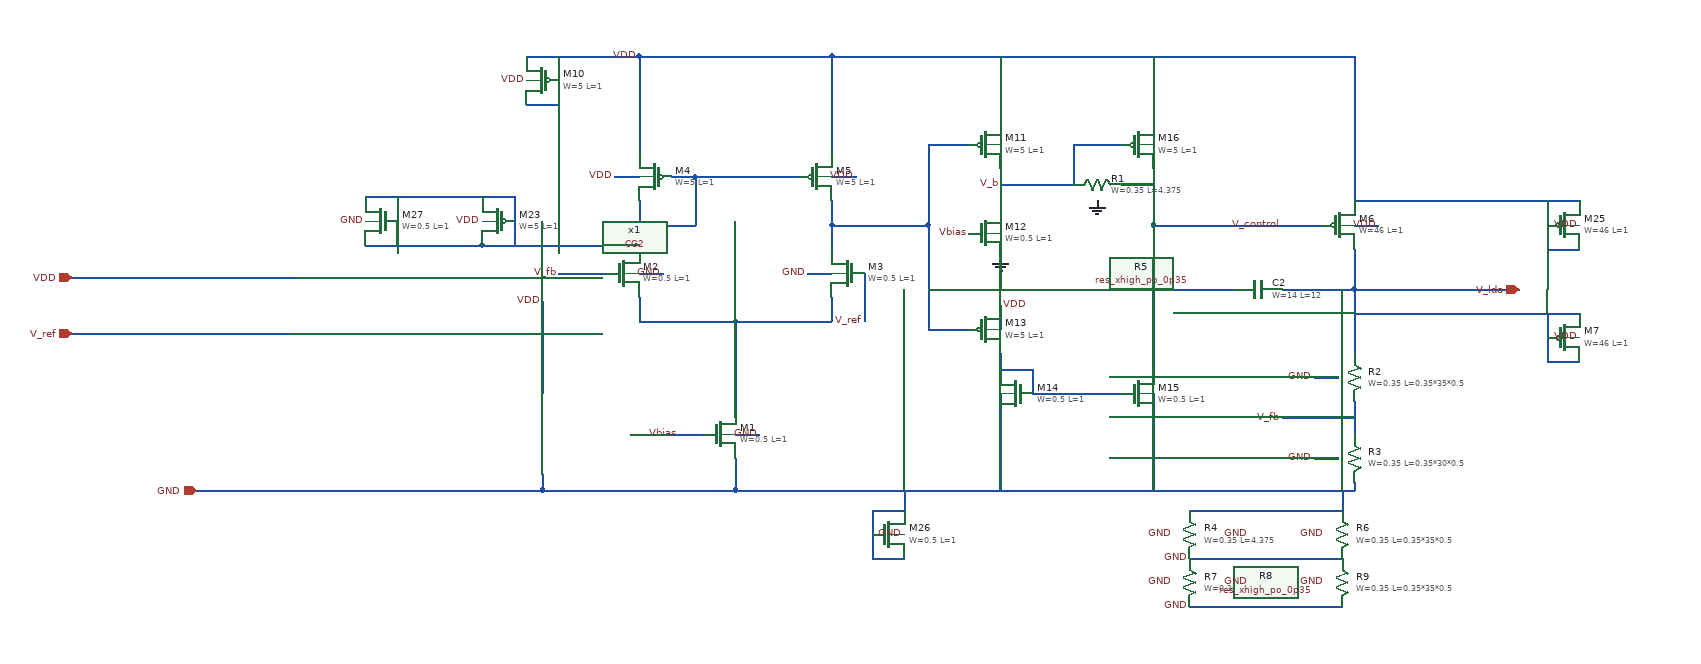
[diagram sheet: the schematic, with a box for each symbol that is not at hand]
v {xschem version=3.4.7 file_version=1.2}
G {}
K {}
V {}
S {}
E {}
N -1385 505 -1385 535 {lab=GND}
N -1585 535 -1385 535 {lab=GND}
N -1385 415 -1385 445 {lab=#net1}
N -1385 325 -1385 355 {lab=#net1}
N -1385 325 -1355 325 {lab=#net1}
N -1355 325 -1325 325 {lab=#net1}
N -1445 325 -1415 325 {lab=#net1}
N -1415 325 -1385 325 {lab=#net1}
N -1385 465 -1355 465 {lab=GND}
N -1475 325 -1445 325 {lab=#net1}
N -1325 325 -1295 325 {lab=#net1}
N -1505 325 -1475 325 {lab=#net1}
N -1295 325 -1265 325 {lab=#net1}
N -1265 295 -1265 325 {lab=#net1}
N -1505 295 -1505 325 {lab=#net1}
N -1505 265 -1475 265 {lab=GND}
N -1295 265 -1265 265 {lab=GND}
N -1505 205 -1505 235 {lab=#net2}
N -1265 205 -1265 235 {lab=#net3}
N -1265 205 -1235 205 {lab=#net3}
N -1505 175 -1505 205 {lab=#net2}
N -1265 175 -1265 205 {lab=#net3}
N -1375 145 -1305 145 {lab=#net2}
N -1505 205 -1475 205 {lab=#net2}
N -1465 145 -1435 145 {lab=#net2}
N -1435 145 -1435 205 {lab=#net2}
N -1435 145 -1375 145 {lab=#net2}
N -1475 205 -1435 205 {lab=#net2}
N -1265 145 -1235 145 {lab=VDD}
N -1535 145 -1505 145 {lab=VDD}
N -1625 535 -1585 535 {lab=GND}
N -1645 535 -1625 535 {lab=GND}
N -1805 535 -1655 535 {lab=GND}
N -1655 535 -1645 535 {lab=GND}
N -1605 265 -1575 265 {lab=V_fb}
N -1575 265 -1545 265 {lab=V_fb}
N -1225 295 -1225 325 {lab=V_ref}
N -1225 265 -1225 295 {lab=V_ref}
N -705 445 -675 445 {lab=V_fb}
N -675 445 -645 445 {lab=V_fb}
N -615 205 -585 205 {lab=VDD}
N -615 125 -615 175 {lab=VDD}
N -615 285 -535 285 {lab=V_ldo}
N -1505 85 -1505 115 {lab=VDD}
N -1265 85 -1265 115 {lab=VDD}
N -1265 -5 -1265 25 {lab=VDD}
N -1505 -5 -1505 25 {lab=VDD}
N -1505 -5 -1265 -5 {lab=VDD}
N -615 55 -615 115 {lab=VDD}
N -615 115 -615 125 {lab=VDD}
N -1385 535 -615 535 {lab=GND}
N -1235 205 -1165 205 {lab=#net3}
N -1055 135 -1055 185 {lab=V_b}
N -1265 -5 -615 -5 {lab=VDD}
N -1055 55 -1055 75 {lab=VDD}
N -1015 385 -1015 415 {lab=#net4}
N -1055 385 -1015 385 {lab=#net4}
N -1145 105 -1095 105 {lab=#net3}
N -1165 205 -1145 205 {lab=#net3}
N -1055 445 -1055 475 {lab=GND}
N -1055 365 -1055 385 {lab=#net4}
N -1015 415 -905 415 {lab=#net4}
N -865 365 -865 385 {lab=V_control}
N -865 445 -865 475 {lab=GND}
N -865 55 -865 75 {lab=VDD}
N -1055 215 -1055 245 {lab=GND}
N -1055 75 -1055 105 {lab=VDD}
N -1055 305 -1055 335 {lab=VDD}
N -1055 415 -1055 445 {lab=GND}
N -905 155 -865 155 {lab=V_control}
N -965 105 -905 105 {lab=V_b}
N -965 105 -965 155 {lab=V_b}
N -865 205 -655 205 {lab=V_control}
N -865 415 -865 445 {lab=GND}
N -865 75 -865 105 {lab=VDD}
N -1145 105 -1145 205 {lab=#net3}
N -865 135 -865 205 {lab=V_control}
N -865 305 -865 365 {lab=V_control}
N -865 205 -865 305 {lab=V_control}
N -1145 205 -1145 335 {lab=#net3}
N -1145 335 -1095 335 {lab=#net3}
N -1145 285 -765 285 {lab=#net3}
N -615 235 -615 285 {lab=V_ldo}
N -645 285 -615 285 {lab=V_ldo}
N -985 155 -965 155 {lab=V_b}
N -1055 155 -1045 155 {lab=V_b}
N -645 445 -615 445 {lab=V_fb}
N -665 395 -635 395 {lab=GND}
N -665 495 -635 495 {lab=GND}
N -615 425 -615 465 {lab=V_fb}
N -615 345 -615 365 {lab=V_ldo}
N -615 525 -615 535 {lab=GND}
N -1895 535 -1805 535 {lab=GND}
N -1515 465 -1425 465 {lab=Vbias}
N -1625 300 -1625 325 {lab=VDD}
N -1625 385 -1625 415 {lab=VDD}
N -1625 515 -1625 535 {lab=GND}
N -1385 495 -1385 505 {lab=GND}
N -535 285 -410 285 {lab=V_ldo}
N -1645 -5 -1505 -5 {lab=VDD}
N -1645 55 -1605 55 {lab=VDD}
N -1605 -5 -1605 55 {lab=VDD}
N -1700 170 -1660 170 {lab=#net2}
N -1660 170 -1660 230 {lab=#net2}
N -1700 230 -1660 230 {lab=#net2}
N -1700 230 -1505 230 {lab=#net2}
N -375 235 -335 235 {lab=VDD}
N -375 175 -375 235 {lab=VDD}
N -1215 620 -1175 620 {lab=GND}
N -1215 560 -1215 620 {lab=GND}
N -1215 560 -1175 560 {lab=GND}
N -1175 535 -1175 560 {lab=GND}
N -820 560 -630 560 {lab=GND}
N -630 535 -630 560 {lab=GND}
N -820 620 -630 620 {lab=GND}
N -820 680 -630 680 {lab=GND}
N -615 -5 -615 55 {lab=VDD}
N -1505 25 -1505 85 {lab=VDD}
N -1265 25 -1265 85 {lab=VDD}
N -1055 -5 -1055 55 {lab=VDD}
N -865 -5 -865 55 {lab=VDD}
N -1055 475 -1055 535 {lab=GND}
N -865 475 -865 535 {lab=GND}
N -1385 355 -1385 415 {lab=#net1}
N -1625 325 -1625 385 {lab=VDD}
N -705 285 -645 285 {lab=V_ldo}
N -615 285 -615 345 {lab=V_ldo}
N -1045 155 -985 155 {lab=V_b}
N -1845 170 -1700 170 {lab=#net2}
N -1845 230 -1700 230 {lab=#net2}
N -1805 170 -1805 230 {lab=#net2}
N -2210 270 -1930 270 {lab=VDD}
N -2210 340 -1940 340 {lab=V_ref}
N -2055 535 -1895 535 {lab=GND}
N -615 175 -335 175 {lab=VDD}
N -375 375 -335 375 {lab=V_ldo}
N -375 315 -375 375 {lab=V_ldo}
N -615 315 -335 315 {lab=V_ldo}
C {sky130_fd_pr/nfet_01v8_lvt.sym} -1405 465 0 0 {name=M1
W=0.5
L=1
nf=1
mult=8
ad="expr('int((@nf + 1)/2) * @W / @nf * 0.29')"
pd="expr('2*int((@nf + 1)/2) * (@W / @nf + 0.29)')"
as="expr('int((@nf + 2)/2) * @W / @nf * 0.29')"
ps="expr('2*int((@nf + 2)/2) * (@W / @nf + 0.29)')"
nrd="expr('0.29 / @W ')" nrs="expr('0.29 / @W ')"
sa=0 sb=0 sd=0
model=nfet_01v8_lvt
spiceprefix=X
}
C {lab_wire.sym} -1625 300 0 0 {name=p1 sig_type=std_logic lab=VDD
}
C {lab_wire.sym} -1355 465 1 1 {name=p2 sig_type=std_logic lab=GND
W=4}
C {sky130_fd_pr/nfet_01v8_lvt.sym} -1525 265 0 0 {name=M2
W=0.5
L=1
nf=1
mult=2
ad="expr('int((@nf + 1)/2) * @W / @nf * 0.29')"
pd="expr('2*int((@nf + 1)/2) * (@W / @nf + 0.29)')"
as="expr('int((@nf + 2)/2) * @W / @nf * 0.29')"
ps="expr('2*int((@nf + 2)/2) * (@W / @nf + 0.29)')"
nrd="expr('0.29 / @W ')" nrs="expr('0.29 / @W ')"
sa=0 sb=0 sd=0
model=nfet_01v8_lvt
spiceprefix=X
}
C {lab_wire.sym} -1475 265 1 1 {name=p4 sig_type=std_logic lab=GND
W=1}
C {sky130_fd_pr/nfet_01v8_lvt.sym} -1245 265 0 1 {name=M3
W=0.5
L=1
nf=1
mult=2
ad="expr('int((@nf + 1)/2) * @W / @nf * 0.29')"
pd="expr('2*int((@nf + 1)/2) * (@W / @nf + 0.29)')"
as="expr('int((@nf + 2)/2) * @W / @nf * 0.29')"
ps="expr('2*int((@nf + 2)/2) * (@W / @nf + 0.29)')"
nrd="expr('0.29 / @W ')" nrs="expr('0.29 / @W ')"
sa=0 sb=0 sd=0
model=nfet_01v8_lvt
spiceprefix=X
}
C {lab_wire.sym} -1295 265 3 0 {name=p6 sig_type=std_logic lab=GND
W=1}
C {sky130_fd_pr/pfet_01v8_lvt.sym} -1485 145 0 1 {name=M4
W=5
L=1
nf=1
mult=2
ad="expr('int((@nf + 1)/2) * @W / @nf * 0.29')"
pd="expr('2*int((@nf + 1)/2) * (@W / @nf + 0.29)')"
as="expr('int((@nf + 2)/2) * @W / @nf * 0.29')"
ps="expr('2*int((@nf + 2)/2) * (@W / @nf + 0.29)')"
nrd="expr('0.29 / @W ')" nrs="expr('0.29 / @W ')"
sa=0 sb=0 sd=0
model=pfet_01v8_lvt
spiceprefix=X
}
C {sky130_fd_pr/pfet_01v8_lvt.sym} -1285 145 0 0 {name=M5
W=5
L=1
nf=1
mult=2
ad="expr('int((@nf + 1)/2) * @W / @nf * 0.29')"
pd="expr('2*int((@nf + 1)/2) * (@W / @nf + 0.29)')"
as="expr('int((@nf + 2)/2) * @W / @nf * 0.29')"
ps="expr('2*int((@nf + 2)/2) * (@W / @nf + 0.29)')"
nrd="expr('0.29 / @W ')" nrs="expr('0.29 / @W ')"
sa=0 sb=0 sd=0
model=pfet_01v8_lvt
spiceprefix=X
}
C {lab_wire.sym} -1235 145 1 1 {name=p5 sig_type=std_logic lab=VDD
W=10}
C {lab_wire.sym} -1535 145 3 0 {name=p7 sig_type=std_logic lab=VDD
W=10}
C {lab_wire.sym} -1455 465 1 1 {name=p9 sig_type=std_logic lab=Vbias
}
C {lab_wire.sym} -1605 265 0 0 {name=p14 sig_type=std_logic lab=V_fb
W=1.7}
C {lab_wire.sym} -1225 325 3 0 {name=p15 sig_type=std_logic lab=V_ref
W=1}
C {sky130_fd_pr/pfet_01v8_lvt.sym} -635 205 0 0 {name=M6
W=46
L=1
nf=1
mult=25
ad="expr('int((@nf + 1)/2) * @W / @nf * 0.29')"
pd="expr('2*int((@nf + 1)/2) * (@W / @nf + 0.29)')"
as="expr('int((@nf + 2)/2) * @W / @nf * 0.29')"
ps="expr('2*int((@nf + 2)/2) * (@W / @nf + 0.29)')"
nrd="expr('0.29 / @W ')" nrs="expr('0.29 / @W ')"
sa=0 sb=0 sd=0
model=pfet_01v8_lvt
spiceprefix=X
}
C {lab_wire.sym} -705 445 0 0 {name=p8 sig_type=std_logic lab=V_fb
}
C {lab_wire.sym} -585 205 1 1 {name=p16 sig_type=std_logic lab=VDD
W=105}
C {lab_wire.sym} -705 205 0 0 {name=p19 sig_type=std_logic lab=V_control
W=210}
C {lab_wire.sym} -1505 -5 0 0 {name=p23 sig_type=std_logic lab=VDD
}
C {sky130_fd_pr/pfet_01v8_lvt.sym} -1075 105 0 0 {name=M11
W=5
L=1
nf=1
mult=6
ad="expr('int((@nf + 1)/2) * @W / @nf * 0.29')"
pd="expr('2*int((@nf + 1)/2) * (@W / @nf + 0.29)')"
as="expr('int((@nf + 2)/2) * @W / @nf * 0.29')"
ps="expr('2*int((@nf + 2)/2) * (@W / @nf + 0.29)')"
nrd="expr('0.29 / @W ')" nrs="expr('0.29 / @W ')"
sa=0 sb=0 sd=0
model=pfet_01v8_lvt
spiceprefix=X
}
C {sky130_fd_pr/nfet_01v8_lvt.sym} -1075 215 0 0 {name=M12
W=0.5
L=1
nf=1
mult=2
ad="expr('int((@nf + 1)/2) * @W / @nf * 0.29')"
pd="expr('2*int((@nf + 1)/2) * (@W / @nf + 0.29)')"
as="expr('int((@nf + 2)/2) * @W / @nf * 0.29')"
ps="expr('2*int((@nf + 2)/2) * (@W / @nf + 0.29)')"
nrd="expr('0.29 / @W ')" nrs="expr('0.29 / @W ')"
sa=0 sb=0 sd=0
model=nfet_01v8_lvt
spiceprefix=X
}
C {lab_wire.sym} -1095 215 2 1 {name=p24 sig_type=std_logic lab=Vbias
}
C {sky130_fd_pr/pfet_01v8_lvt.sym} -1075 335 0 0 {name=M13
W=5
L=1
nf=1
mult=6
ad="expr('int((@nf + 1)/2) * @W / @nf * 0.29')"
pd="expr('2*int((@nf + 1)/2) * (@W / @nf + 0.29)')"
as="expr('int((@nf + 2)/2) * @W / @nf * 0.29')"
ps="expr('2*int((@nf + 2)/2) * (@W / @nf + 0.29)')"
nrd="expr('0.29 / @W ')" nrs="expr('0.29 / @W ')"
sa=0 sb=0 sd=0
model=pfet_01v8_lvt
spiceprefix=X
}
C {lab_wire.sym} -1055 305 0 1 {name=p27 sig_type=std_logic lab=VDD
}
C {sky130_fd_pr/nfet_01v8_lvt.sym} -1035 415 0 1 {name=M14
W=0.5
L=1
nf=1
mult=2
ad="expr('int((@nf + 1)/2) * @W / @nf * 0.29')"
pd="expr('2*int((@nf + 1)/2) * (@W / @nf + 0.29)')"
as="expr('int((@nf + 2)/2) * @W / @nf * 0.29')"
ps="expr('2*int((@nf + 2)/2) * (@W / @nf + 0.29)')"
nrd="expr('0.29 / @W ')" nrs="expr('0.29 / @W ')"
sa=0 sb=0 sd=0
model=nfet_01v8_lvt
spiceprefix=X
}
C {sky130_fd_pr/nfet_01v8_lvt.sym} -885 415 0 0 {name=M15
W=0.5
L=1
nf=1
mult=4
ad="expr('int((@nf + 1)/2) * @W / @nf * 0.29')"
pd="expr('2*int((@nf + 1)/2) * (@W / @nf + 0.29)')"
as="expr('int((@nf + 2)/2) * @W / @nf * 0.29')"
ps="expr('2*int((@nf + 2)/2) * (@W / @nf + 0.29)')"
nrd="expr('0.29 / @W ')" nrs="expr('0.29 / @W ')"
sa=0 sb=0 sd=0
model=nfet_01v8_lvt
spiceprefix=X
}
C {sky130_fd_pr/pfet_01v8_lvt.sym} -885 105 0 0 {name=M16
W=5
L=1
nf=1
mult=6
ad="expr('int((@nf + 1)/2) * @W / @nf * 0.29')"
pd="expr('2*int((@nf + 1)/2) * (@W / @nf + 0.29)')"
as="expr('int((@nf + 2)/2) * @W / @nf * 0.29')"
ps="expr('2*int((@nf + 2)/2) * (@W / @nf + 0.29)')"
nrd="expr('0.29 / @W ')" nrs="expr('0.29 / @W ')"
sa=0 sb=0 sd=0
model=pfet_01v8_lvt
spiceprefix=X
}
C {gnd.sym} -1055 245 0 0 {name=l1 lab=GND}
C {sky130_fd_pr/res_xhigh_po_0p35.sym} -935 155 3 0 {name=R1
W=0.35
L=4.375
model=res_xhigh_po_0p35
spiceprefix=X
 mult=1}
C {gnd.sym} -935 175 0 0 {name=l2 lab=GND}
C {lab_wire.sym} -1055 155 0 0 {name=p25 sig_type=std_logic lab=V_b

}
C {sky130_fd_pr/cap_mim_m3_1.sym} -735 285 1 0 {name=C2 model=cap_mim_m3_1 W=14 L=12 MF=9 spiceprefix=X}
C {lab_wire.sym} -665 395 3 0 {name=p28 sig_type=std_logic lab=GND
}
C {sky130_fd_pr/res_xhigh_po_0p35.sym} -615 395 0 0 {name=R2
W=0.35
L=0.35*35*0.5
model=res_xhigh_po_0p35
spiceprefix=X
 mult=1}
C {lab_wire.sym} -665 495 3 0 {name=p29 sig_type=std_logic lab=GND
}
C {sky130_fd_pr/res_xhigh_po_0p35.sym} -615 495 0 0 {name=R3
W=0.35
L=0.35*30*0.5
model=res_xhigh_po_0p35
spiceprefix=X
 mult=1}
C {sky130_fd_pr/pfet_01v8_lvt.sym} -1625 25 0 1 {name=M10
W=5
L=1
nf=1
mult=60
ad="expr('int((@nf + 1)/2) * @W / @nf * 0.29')"
pd="expr('2*int((@nf + 1)/2) * (@W / @nf + 0.29)')"
as="expr('int((@nf + 2)/2) * @W / @nf * 0.29')"
ps="expr('2*int((@nf + 2)/2) * (@W / @nf + 0.29)')"
nrd="expr('0.29 / @W ')" nrs="expr('0.29 / @W ')"
sa=0 sb=0 sd=0
model=pfet_01v8_lvt
spiceprefix=X
}
C {sky130_fd_pr/pfet_01v8_lvt.sym} -1680 200 0 1 {name=M23
W=5
L=1
nf=1
mult=2
ad="expr('int((@nf + 1)/2) * @W / @nf * 0.29')"
pd="expr('2*int((@nf + 1)/2) * (@W / @nf + 0.29)')"
as="expr('int((@nf + 2)/2) * @W / @nf * 0.29')"
ps="expr('2*int((@nf + 2)/2) * (@W / @nf + 0.29)')"
nrd="expr('0.29 / @W ')" nrs="expr('0.29 / @W ')"
sa=0 sb=0 sd=0
model=pfet_01v8_lvt
spiceprefix=X
}
C {lab_wire.sym} -1700 200 3 0 {name=p12 sig_type=std_logic lab=VDD
W=10}
C {sky130_fd_pr/pfet_01v8_lvt.sym} -355 205 0 0 {name=M25
W=46
L=1
nf=1
mult=1
ad="expr('int((@nf + 1)/2) * @W / @nf * 0.29')"
pd="expr('2*int((@nf + 1)/2) * (@W / @nf + 0.29)')"
as="expr('int((@nf + 2)/2) * @W / @nf * 0.29')"
ps="expr('2*int((@nf + 2)/2) * (@W / @nf + 0.29)')"
nrd="expr('0.29 / @W ')" nrs="expr('0.29 / @W ')"
sa=0 sb=0 sd=0
model=pfet_01v8_lvt
spiceprefix=X
}
C {lab_wire.sym} -1645 25 3 0 {name=p36 sig_type=std_logic lab=VDD
W=10}
C {sky130_fd_pr/nfet_01v8_lvt.sym} -1195 590 0 0 {name=M26
W=0.5
L=1
nf=1
mult=56
ad="expr('int((@nf + 1)/2) * @W / @nf * 0.29')"
pd="expr('2*int((@nf + 1)/2) * (@W / @nf + 0.29)')"
as="expr('int((@nf + 2)/2) * @W / @nf * 0.29')"
ps="expr('2*int((@nf + 2)/2) * (@W / @nf + 0.29)')"
nrd="expr('0.29 / @W ')" nrs="expr('0.29 / @W ')"
sa=0 sb=0 sd=0
model=nfet_01v8_lvt
spiceprefix=X
}
C {lab_wire.sym} -1175 590 1 1 {name=p37 sig_type=std_logic lab=GND
W=4}
C {sky130_fd_pr/res_xhigh_po_0p35.sym} -820 590 0 0 {name=R4
W=0.35
L=4.375
model=res_xhigh_po_0p35
spiceprefix=X
 mult=1}
C {sky130_fd_pr/res_xhigh_po_0p35.sym} -725 590 0 0 {name=R5
W=0.35
L=0.35*30*0.5
model=res_xhigh_po_0p35
spiceprefix=X
 mult=1}
C {sky130_fd_pr/res_xhigh_po_0p35.sym} -630 590 0 0 {name=R6
W=0.35
L=0.35*35*0.5
model=res_xhigh_po_0p35
spiceprefix=X
 mult=1}
C {lab_wire.sym} -840 590 3 0 {name=p38 sig_type=std_logic lab=GND
}
C {lab_wire.sym} -745 590 3 0 {name=p39 sig_type=std_logic lab=GND
}
C {lab_wire.sym} -650 590 3 0 {name=p40 sig_type=std_logic lab=GND
}
C {sky130_fd_pr/res_xhigh_po_0p35.sym} -820 650 0 0 {name=R7
W=0.35
L=4.375
model=res_xhigh_po_0p35
spiceprefix=X
 mult=1}
C {sky130_fd_pr/res_xhigh_po_0p35.sym} -725 650 0 0 {name=R8
W=0.35
L=0.35*30*0.5
model=res_xhigh_po_0p35
spiceprefix=X
 mult=1}
C {sky130_fd_pr/res_xhigh_po_0p35.sym} -630 650 0 0 {name=R9
W=0.35
L=0.35*35*0.5
model=res_xhigh_po_0p35
spiceprefix=X
 mult=1}
C {lab_wire.sym} -840 650 3 0 {name=p41 sig_type=std_logic lab=GND
}
C {lab_wire.sym} -745 650 3 0 {name=p42 sig_type=std_logic lab=GND
}
C {lab_wire.sym} -650 650 3 0 {name=p43 sig_type=std_logic lab=GND
}
C {lab_wire.sym} -820 620 0 0 {name=p44 sig_type=std_logic lab=GND
}
C {lab_wire.sym} -820 680 0 0 {name=p45 sig_type=std_logic lab=GND
}
C {lab_wire.sym} -335 205 1 1 {name=p17 sig_type=std_logic lab=VDD
W=105}
C {sky130_fd_pr/nfet_01v8_lvt.sym} -1825 200 0 1 {name=M27
W=0.5
L=1
nf=1
mult=2
ad="expr('int((@nf + 1)/2) * @W / @nf * 0.29')"
pd="expr('2*int((@nf + 1)/2) * (@W / @nf + 0.29)')"
as="expr('int((@nf + 2)/2) * @W / @nf * 0.29')"
ps="expr('2*int((@nf + 2)/2) * (@W / @nf + 0.29)')"
nrd="expr('0.29 / @W ')" nrs="expr('0.29 / @W ')"
sa=0 sb=0 sd=0
model=nfet_01v8_lvt
spiceprefix=X
}
C {lab_wire.sym} -1845 200 3 0 {name=p35 sig_type=std_logic lab=GND
W=1}
C {iopin.sym} -2210 270 2 0 {name=p34 lab=VDD
}
C {iopin.sym} -2210 340 2 0 {name=p46 lab=V_ref
}
C {iopin.sym} -410 285 0 0 {name=p10 lab=V_ldo
}
C {iopin.sym} -2055 535 2 0 {name=p11 lab=GND
}
C {sky130_fd_pr/pfet_01v8_lvt.sym} -355 345 0 0 {name=M7
W=46
L=1
nf=1
mult=1
ad="expr('int((@nf + 1)/2) * @W / @nf * 0.29')"
pd="expr('2*int((@nf + 1)/2) * (@W / @nf + 0.29)')"
as="expr('int((@nf + 2)/2) * @W / @nf * 0.29')"
ps="expr('2*int((@nf + 2)/2) * (@W / @nf + 0.29)')"
nrd="expr('0.29 / @W ')" nrs="expr('0.29 / @W ')"
sa=0 sb=0 sd=0
model=pfet_01v8_lvt
spiceprefix=X
}
C {lab_wire.sym} -335 345 1 1 {name=p3 sig_type=std_logic lab=VDD
W=105}
C {/foss/designs/CG2.sym} -1665 465 0 0 {name=x1}
